VERSION 5.7 ;
  NOWIREEXTENSIONATPIN ON ;
  DIVIDERCHAR "/" ;
  BUSBITCHARS "[]" ;
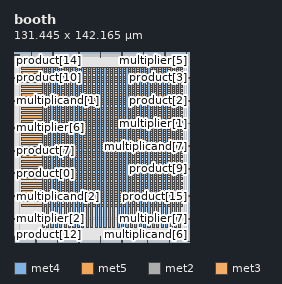
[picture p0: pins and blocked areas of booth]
MACRO booth
  CLASS BLOCK ;
  FOREIGN booth ;
  ORIGIN 0.000 0.000 ;
  SIZE 131.445 BY 142.165 ;
  PIN VGND
    DIRECTION INOUT ;
    USE GROUND ;
    PORT
      LAYER met4 ;
        RECT 24.340 10.640 25.940 130.800 ;
    END
    PORT
      LAYER met4 ;
        RECT 30.940 10.640 32.540 130.800 ;
    END
    PORT
      LAYER met4 ;
        RECT 37.540 10.640 39.140 130.800 ;
    END
    PORT
      LAYER met4 ;
        RECT 44.140 10.640 45.740 130.800 ;
    END
    PORT
      LAYER met4 ;
        RECT 50.740 10.640 52.340 130.800 ;
    END
    PORT
      LAYER met4 ;
        RECT 57.340 10.640 58.940 130.800 ;
    END
    PORT
      LAYER met4 ;
        RECT 63.940 10.640 65.540 130.800 ;
    END
    PORT
      LAYER met4 ;
        RECT 70.540 10.640 72.140 130.800 ;
    END
    PORT
      LAYER met4 ;
        RECT 77.140 10.640 78.740 130.800 ;
    END
    PORT
      LAYER met4 ;
        RECT 83.740 10.640 85.340 130.800 ;
    END
    PORT
      LAYER met4 ;
        RECT 90.340 10.640 91.940 130.800 ;
    END
    PORT
      LAYER met4 ;
        RECT 96.940 10.640 98.540 130.800 ;
    END
    PORT
      LAYER met4 ;
        RECT 103.540 10.640 105.140 130.800 ;
    END
    PORT
      LAYER met4 ;
        RECT 110.140 10.640 111.740 130.800 ;
    END
    PORT
      LAYER met4 ;
        RECT 116.740 10.640 118.340 130.800 ;
    END
    PORT
      LAYER met4 ;
        RECT 123.340 10.640 124.940 130.800 ;
    END
    PORT
      LAYER met5 ;
        RECT 5.280 30.030 125.820 31.630 ;
    END
    PORT
      LAYER met5 ;
        RECT 5.280 36.630 125.820 38.230 ;
    END
    PORT
      LAYER met5 ;
        RECT 5.280 43.230 125.820 44.830 ;
    END
    PORT
      LAYER met5 ;
        RECT 5.280 49.830 125.820 51.430 ;
    END
    PORT
      LAYER met5 ;
        RECT 5.280 56.430 125.820 58.030 ;
    END
    PORT
      LAYER met5 ;
        RECT 5.280 63.030 125.820 64.630 ;
    END
    PORT
      LAYER met5 ;
        RECT 5.280 69.630 125.820 71.230 ;
    END
    PORT
      LAYER met5 ;
        RECT 5.280 76.230 125.820 77.830 ;
    END
    PORT
      LAYER met5 ;
        RECT 5.280 82.830 125.820 84.430 ;
    END
    PORT
      LAYER met5 ;
        RECT 5.280 89.430 125.820 91.030 ;
    END
    PORT
      LAYER met5 ;
        RECT 5.280 96.030 125.820 97.630 ;
    END
    PORT
      LAYER met5 ;
        RECT 5.280 102.630 125.820 104.230 ;
    END
    PORT
      LAYER met5 ;
        RECT 5.280 109.230 125.820 110.830 ;
    END
    PORT
      LAYER met5 ;
        RECT 5.280 115.830 125.820 117.430 ;
    END
    PORT
      LAYER met5 ;
        RECT 5.280 122.430 125.820 124.030 ;
    END
    PORT
      LAYER met5 ;
        RECT 5.280 129.030 125.820 130.630 ;
    END
  END VGND
  PIN VPWR
    DIRECTION INOUT ;
    USE POWER ;
    PORT
      LAYER met4 ;
        RECT 21.040 10.640 22.640 130.800 ;
    END
    PORT
      LAYER met4 ;
        RECT 27.640 10.640 29.240 130.800 ;
    END
    PORT
      LAYER met4 ;
        RECT 34.240 10.640 35.840 130.800 ;
    END
    PORT
      LAYER met4 ;
        RECT 40.840 10.640 42.440 130.800 ;
    END
    PORT
      LAYER met4 ;
        RECT 47.440 10.640 49.040 130.800 ;
    END
    PORT
      LAYER met4 ;
        RECT 54.040 10.640 55.640 130.800 ;
    END
    PORT
      LAYER met4 ;
        RECT 60.640 10.640 62.240 130.800 ;
    END
    PORT
      LAYER met4 ;
        RECT 67.240 10.640 68.840 130.800 ;
    END
    PORT
      LAYER met4 ;
        RECT 73.840 10.640 75.440 130.800 ;
    END
    PORT
      LAYER met4 ;
        RECT 80.440 10.640 82.040 130.800 ;
    END
    PORT
      LAYER met4 ;
        RECT 87.040 10.640 88.640 130.800 ;
    END
    PORT
      LAYER met4 ;
        RECT 93.640 10.640 95.240 130.800 ;
    END
    PORT
      LAYER met4 ;
        RECT 100.240 10.640 101.840 130.800 ;
    END
    PORT
      LAYER met4 ;
        RECT 106.840 10.640 108.440 130.800 ;
    END
    PORT
      LAYER met4 ;
        RECT 113.440 10.640 115.040 130.800 ;
    END
    PORT
      LAYER met4 ;
        RECT 120.040 10.640 121.640 130.800 ;
    END
    PORT
      LAYER met5 ;
        RECT 5.280 26.730 125.820 28.330 ;
    END
    PORT
      LAYER met5 ;
        RECT 5.280 33.330 125.820 34.930 ;
    END
    PORT
      LAYER met5 ;
        RECT 5.280 39.930 125.820 41.530 ;
    END
    PORT
      LAYER met5 ;
        RECT 5.280 46.530 125.820 48.130 ;
    END
    PORT
      LAYER met5 ;
        RECT 5.280 53.130 125.820 54.730 ;
    END
    PORT
      LAYER met5 ;
        RECT 5.280 59.730 125.820 61.330 ;
    END
    PORT
      LAYER met5 ;
        RECT 5.280 66.330 125.820 67.930 ;
    END
    PORT
      LAYER met5 ;
        RECT 5.280 72.930 125.820 74.530 ;
    END
    PORT
      LAYER met5 ;
        RECT 5.280 79.530 125.820 81.130 ;
    END
    PORT
      LAYER met5 ;
        RECT 5.280 86.130 125.820 87.730 ;
    END
    PORT
      LAYER met5 ;
        RECT 5.280 92.730 125.820 94.330 ;
    END
    PORT
      LAYER met5 ;
        RECT 5.280 99.330 125.820 100.930 ;
    END
    PORT
      LAYER met5 ;
        RECT 5.280 105.930 125.820 107.530 ;
    END
    PORT
      LAYER met5 ;
        RECT 5.280 112.530 125.820 114.130 ;
    END
    PORT
      LAYER met5 ;
        RECT 5.280 119.130 125.820 120.730 ;
    END
    PORT
      LAYER met5 ;
        RECT 5.280 125.730 125.820 127.330 ;
    END
  END VPWR
  PIN multiplicand[0]
    DIRECTION INPUT ;
    USE SIGNAL ;
    ANTENNAGATEAREA 0.213000 ;
    PORT
      LAYER met2 ;
        RECT 128.890 138.165 129.170 142.165 ;
    END
  END multiplicand[0]
  PIN multiplicand[1]
    DIRECTION INPUT ;
    USE SIGNAL ;
    ANTENNAGATEAREA 0.126000 ;
    PORT
      LAYER met3 ;
        RECT 0.000 105.440 4.000 106.040 ;
    END
  END multiplicand[1]
  PIN multiplicand[2]
    DIRECTION INPUT ;
    USE SIGNAL ;
    ANTENNAGATEAREA 0.990000 ;
    PORT
      LAYER met3 ;
        RECT 0.000 34.040 4.000 34.640 ;
    END
  END multiplicand[2]
  PIN multiplicand[3]
    DIRECTION INPUT ;
    USE SIGNAL ;
    ANTENNAGATEAREA 0.495000 ;
    PORT
      LAYER met2 ;
        RECT 64.490 0.000 64.770 4.000 ;
    END
  END multiplicand[3]
  PIN multiplicand[4]
    DIRECTION INPUT ;
    USE SIGNAL ;
    ANTENNAGATEAREA 0.126000 ;
    PORT
      LAYER met2 ;
        RECT 29.070 138.165 29.350 142.165 ;
    END
  END multiplicand[4]
  PIN multiplicand[5]
    DIRECTION INPUT ;
    USE SIGNAL ;
    ANTENNAGATEAREA 0.213000 ;
    PORT
      LAYER met2 ;
        RECT 80.590 138.165 80.870 142.165 ;
    END
  END multiplicand[5]
  PIN multiplicand[6]
    DIRECTION INPUT ;
    USE SIGNAL ;
    ANTENNAGATEAREA 0.247500 ;
    PORT
      LAYER met2 ;
        RECT 116.010 0.000 116.290 4.000 ;
    END
  END multiplicand[6]
  PIN multiplicand[7]
    DIRECTION INPUT ;
    USE SIGNAL ;
    ANTENNAGATEAREA 0.126000 ;
    PORT
      LAYER met3 ;
        RECT 127.445 71.440 131.445 72.040 ;
    END
  END multiplicand[7]
  PIN multiplier[0]
    DIRECTION INPUT ;
    USE SIGNAL ;
    ANTENNAGATEAREA 0.159000 ;
    PORT
      LAYER met2 ;
        RECT 99.910 0.000 100.190 4.000 ;
    END
  END multiplier[0]
  PIN multiplier[1]
    DIRECTION INPUT ;
    USE SIGNAL ;
    ANTENNAGATEAREA 0.213000 ;
    PORT
      LAYER met3 ;
        RECT 127.445 88.440 131.445 89.040 ;
    END
  END multiplier[1]
  PIN multiplier[2]
    DIRECTION INPUT ;
    USE SIGNAL ;
    ANTENNAGATEAREA 0.213000 ;
    PORT
      LAYER met3 ;
        RECT 0.000 17.040 4.000 17.640 ;
    END
  END multiplier[2]
  PIN multiplier[3]
    DIRECTION INPUT ;
    USE SIGNAL ;
    ANTENNAGATEAREA 0.159000 ;
    PORT
      LAYER met2 ;
        RECT 0.090 0.000 0.370 4.000 ;
    END
  END multiplier[3]
  PIN multiplier[4]
    DIRECTION INPUT ;
    USE SIGNAL ;
    ANTENNAGATEAREA 0.126000 ;
    PORT
      LAYER met2 ;
        RECT 96.690 138.165 96.970 142.165 ;
    END
  END multiplier[4]
  PIN multiplier[5]
    DIRECTION INPUT ;
    USE SIGNAL ;
    ANTENNAGATEAREA 0.213000 ;
    PORT
      LAYER met2 ;
        RECT 112.790 138.165 113.070 142.165 ;
    END
  END multiplier[5]
  PIN multiplier[6]
    DIRECTION INPUT ;
    USE SIGNAL ;
    ANTENNAGATEAREA 0.213000 ;
    PORT
      LAYER met3 ;
        RECT 0.000 85.040 4.000 85.640 ;
    END
  END multiplier[6]
  PIN multiplier[7]
    DIRECTION INPUT ;
    USE SIGNAL ;
    ANTENNAGATEAREA 0.196500 ;
    PORT
      LAYER met3 ;
        RECT 127.445 17.040 131.445 17.640 ;
    END
  END multiplier[7]
  PIN product[0]
    DIRECTION OUTPUT TRISTATE ;
    USE SIGNAL ;
    ANTENNADIFFAREA 0.795200 ;
    PORT
      LAYER met3 ;
        RECT 0.000 51.040 4.000 51.640 ;
    END
  END product[0]
  PIN product[10]
    DIRECTION OUTPUT TRISTATE ;
    USE SIGNAL ;
    ANTENNADIFFAREA 0.795200 ;
    PORT
      LAYER met3 ;
        RECT 0.000 122.440 4.000 123.040 ;
    END
  END product[10]
  PIN product[11]
    DIRECTION OUTPUT TRISTATE ;
    USE SIGNAL ;
    ANTENNADIFFAREA 0.795200 ;
    PORT
      LAYER met3 ;
        RECT 127.445 0.040 131.445 0.640 ;
    END
  END product[11]
  PIN product[12]
    DIRECTION OUTPUT TRISTATE ;
    USE SIGNAL ;
    ANTENNADIFFAREA 0.795200 ;
    PORT
      LAYER met2 ;
        RECT 16.190 0.000 16.470 4.000 ;
    END
  END product[12]
  PIN product[13]
    DIRECTION OUTPUT TRISTATE ;
    USE SIGNAL ;
    ANTENNADIFFAREA 1.336500 ;
    PORT
      LAYER met2 ;
        RECT 32.290 0.000 32.570 4.000 ;
    END
  END product[13]
  PIN product[14]
    DIRECTION OUTPUT TRISTATE ;
    USE SIGNAL ;
    ANTENNADIFFAREA 1.336500 ;
    PORT
      LAYER met2 ;
        RECT 12.970 138.165 13.250 142.165 ;
    END
  END product[14]
  PIN product[15]
    DIRECTION OUTPUT TRISTATE ;
    USE SIGNAL ;
    ANTENNADIFFAREA 1.336500 ;
    PORT
      LAYER met3 ;
        RECT 127.445 34.040 131.445 34.640 ;
    END
  END product[15]
  PIN product[1]
    DIRECTION OUTPUT TRISTATE ;
    USE SIGNAL ;
    ANTENNADIFFAREA 0.795200 ;
    PORT
      LAYER met2 ;
        RECT 48.390 0.000 48.670 4.000 ;
    END
  END product[1]
  PIN product[2]
    DIRECTION OUTPUT TRISTATE ;
    USE SIGNAL ;
    ANTENNADIFFAREA 0.795200 ;
    PORT
      LAYER met3 ;
        RECT 127.445 105.440 131.445 106.040 ;
    END
  END product[2]
  PIN product[3]
    DIRECTION OUTPUT TRISTATE ;
    USE SIGNAL ;
    ANTENNADIFFAREA 0.795200 ;
    PORT
      LAYER met3 ;
        RECT 127.445 122.440 131.445 123.040 ;
    END
  END product[3]
  PIN product[4]
    DIRECTION OUTPUT TRISTATE ;
    USE SIGNAL ;
    ANTENNADIFFAREA 0.795200 ;
    PORT
      LAYER met2 ;
        RECT 48.390 138.165 48.670 142.165 ;
    END
  END product[4]
  PIN product[5]
    DIRECTION OUTPUT TRISTATE ;
    USE SIGNAL ;
    ANTENNADIFFAREA 0.795200 ;
    PORT
      LAYER met2 ;
        RECT 64.490 138.165 64.770 142.165 ;
    END
  END product[5]
  PIN product[6]
    DIRECTION OUTPUT TRISTATE ;
    USE SIGNAL ;
    ANTENNADIFFAREA 0.795200 ;
    PORT
      LAYER met2 ;
        RECT 80.590 0.000 80.870 4.000 ;
    END
  END product[6]
  PIN product[7]
    DIRECTION OUTPUT TRISTATE ;
    USE SIGNAL ;
    ANTENNADIFFAREA 0.795200 ;
    PORT
      LAYER met3 ;
        RECT 0.000 68.040 4.000 68.640 ;
    END
  END product[7]
  PIN product[8]
    DIRECTION OUTPUT TRISTATE ;
    USE SIGNAL ;
    ANTENNADIFFAREA 0.795200 ;
    PORT
      LAYER met3 ;
        RECT 0.000 139.440 4.000 140.040 ;
    END
  END product[8]
  PIN product[9]
    DIRECTION OUTPUT TRISTATE ;
    USE SIGNAL ;
    ANTENNADIFFAREA 0.795200 ;
    PORT
      LAYER met3 ;
        RECT 127.445 54.440 131.445 55.040 ;
    END
  END product[9]
  OBS
      LAYER li1 ;
        RECT 5.520 10.795 125.580 130.645 ;
      LAYER met1 ;
        RECT 0.070 10.640 129.190 130.800 ;
      LAYER met2 ;
        RECT 0.100 137.885 12.690 139.925 ;
        RECT 13.530 137.885 28.790 139.925 ;
        RECT 29.630 137.885 48.110 139.925 ;
        RECT 48.950 137.885 64.210 139.925 ;
        RECT 65.050 137.885 80.310 139.925 ;
        RECT 81.150 137.885 96.410 139.925 ;
        RECT 97.250 137.885 112.510 139.925 ;
        RECT 113.350 137.885 128.610 139.925 ;
        RECT 0.100 4.280 129.160 137.885 ;
        RECT 0.650 0.155 15.910 4.280 ;
        RECT 16.750 0.155 32.010 4.280 ;
        RECT 32.850 0.155 48.110 4.280 ;
        RECT 48.950 0.155 64.210 4.280 ;
        RECT 65.050 0.155 80.310 4.280 ;
        RECT 81.150 0.155 99.630 4.280 ;
        RECT 100.470 0.155 115.730 4.280 ;
        RECT 116.570 0.155 129.160 4.280 ;
      LAYER met3 ;
        RECT 4.400 139.040 127.445 139.905 ;
        RECT 4.000 123.440 127.445 139.040 ;
        RECT 4.400 122.040 127.045 123.440 ;
        RECT 4.000 106.440 127.445 122.040 ;
        RECT 4.400 105.040 127.045 106.440 ;
        RECT 4.000 89.440 127.445 105.040 ;
        RECT 4.000 88.040 127.045 89.440 ;
        RECT 4.000 86.040 127.445 88.040 ;
        RECT 4.400 84.640 127.445 86.040 ;
        RECT 4.000 72.440 127.445 84.640 ;
        RECT 4.000 71.040 127.045 72.440 ;
        RECT 4.000 69.040 127.445 71.040 ;
        RECT 4.400 67.640 127.445 69.040 ;
        RECT 4.000 55.440 127.445 67.640 ;
        RECT 4.000 54.040 127.045 55.440 ;
        RECT 4.000 52.040 127.445 54.040 ;
        RECT 4.400 50.640 127.445 52.040 ;
        RECT 4.000 35.040 127.445 50.640 ;
        RECT 4.400 33.640 127.045 35.040 ;
        RECT 4.000 18.040 127.445 33.640 ;
        RECT 4.400 16.640 127.045 18.040 ;
        RECT 4.000 1.040 127.445 16.640 ;
        RECT 4.000 0.175 127.045 1.040 ;
      LAYER met4 ;
        RECT 39.855 32.815 40.440 97.065 ;
        RECT 42.840 32.815 43.740 97.065 ;
        RECT 46.140 32.815 47.040 97.065 ;
        RECT 49.440 32.815 50.340 97.065 ;
        RECT 52.740 32.815 53.640 97.065 ;
        RECT 56.040 32.815 56.940 97.065 ;
        RECT 59.340 32.815 60.240 97.065 ;
        RECT 62.640 32.815 63.540 97.065 ;
        RECT 65.940 32.815 66.840 97.065 ;
        RECT 69.240 32.815 70.140 97.065 ;
        RECT 72.540 32.815 73.440 97.065 ;
        RECT 75.840 32.815 76.740 97.065 ;
        RECT 79.140 32.815 80.040 97.065 ;
        RECT 82.440 32.815 83.340 97.065 ;
        RECT 85.740 32.815 86.185 97.065 ;
  END
END booth
END LIBRARY

